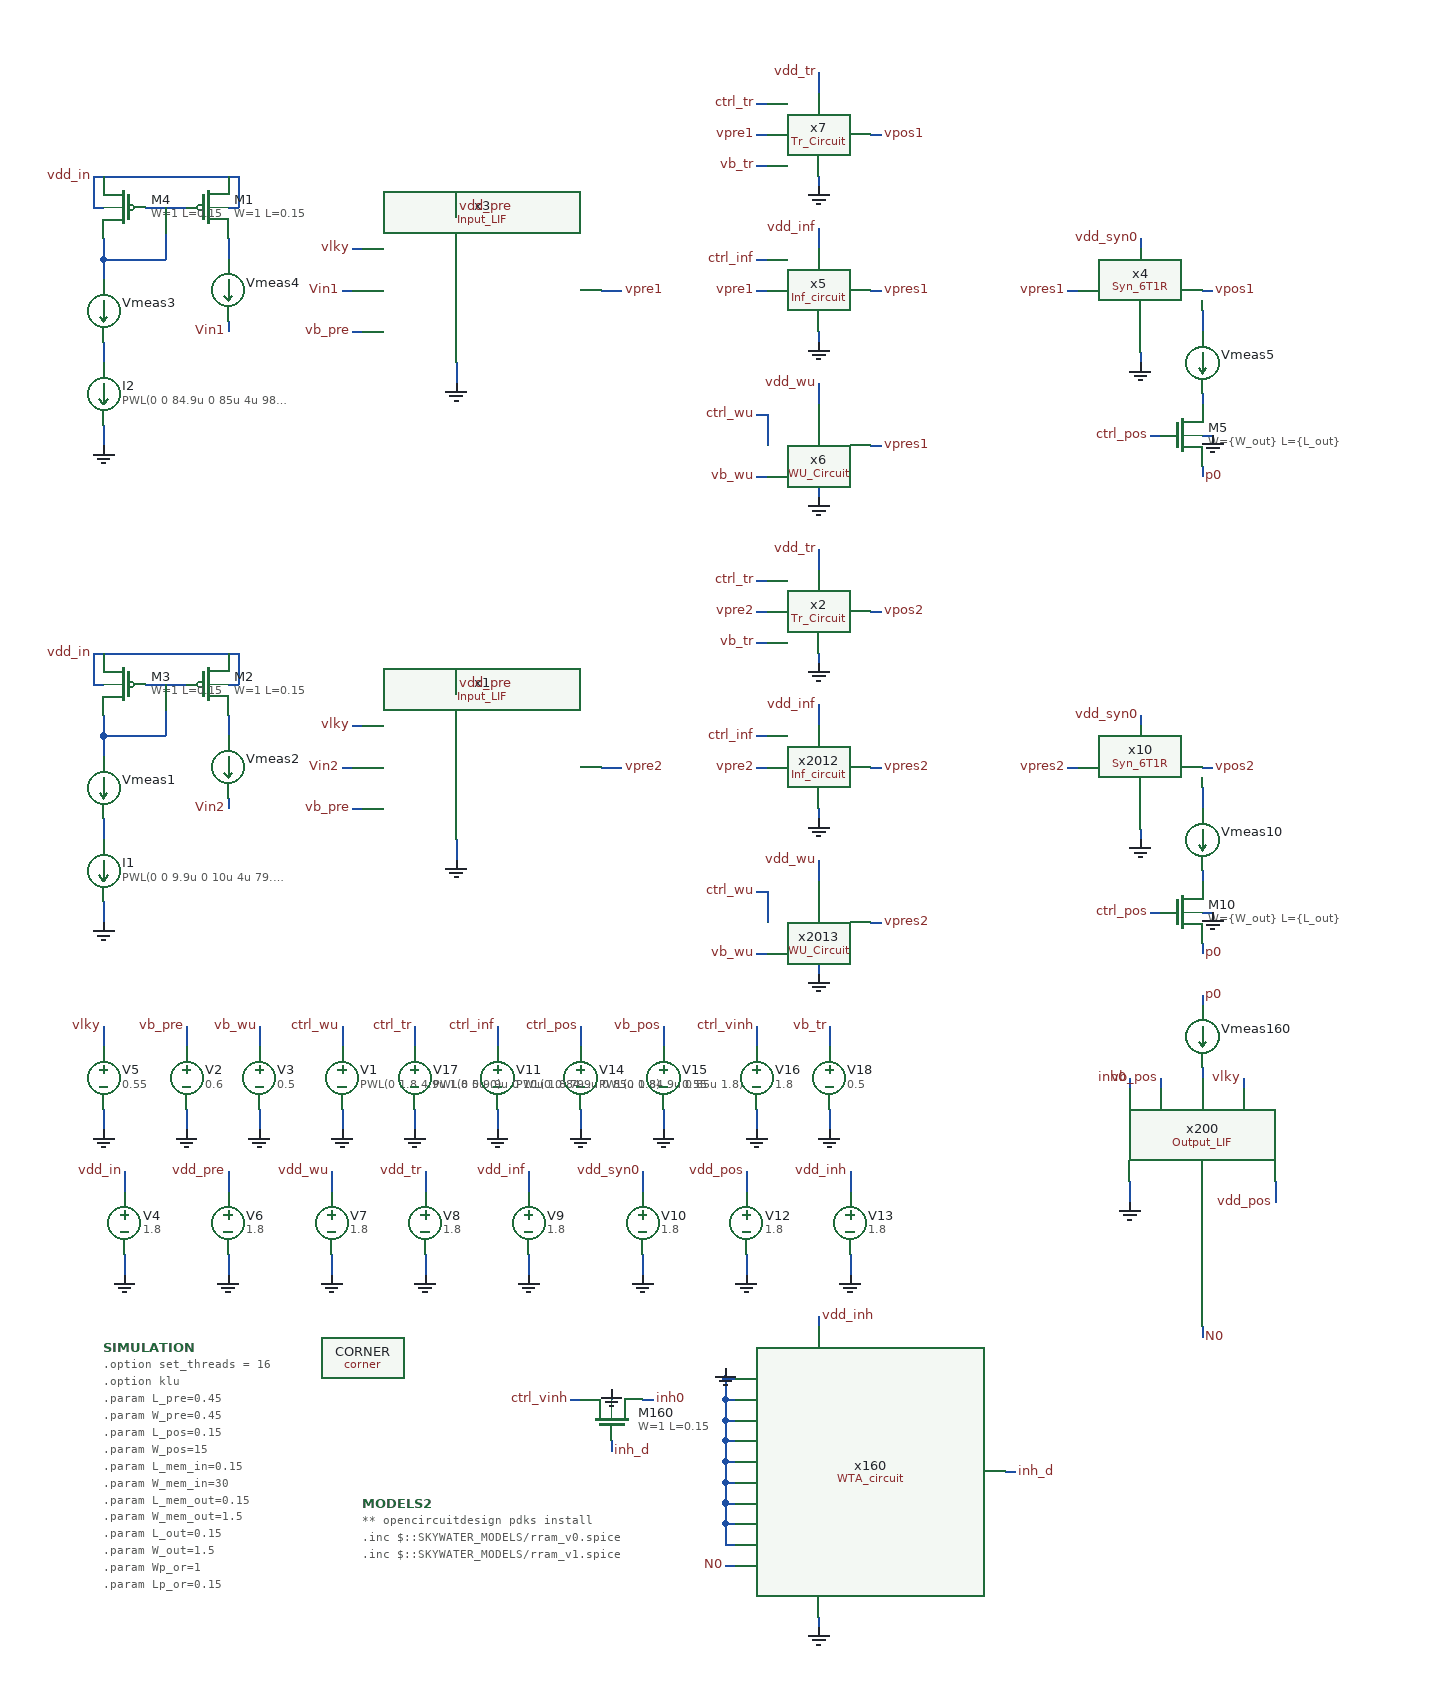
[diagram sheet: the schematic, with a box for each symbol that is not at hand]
v {xschem version=3.4.5 file_version=1.2
}
G {}
K {}
V {}
S {}
E {}
B 2 -1600 -1600 -800 -1200 {flags=graph
y1=0
y2=4e-06
ypos1=0
ypos2=2
divy=5
subdivy=1
unity=1
x1=8.43669e-05
x2=8.60304e-05
divx=5
subdivx=1
xlabmag=1.0
ylabmag=1.0


dataset=-1
unitx=1
logx=0
logy=0



color=4
node=i(Vmeas1)}
B 2 -1600 -1200 -800 -800 {flags=graph
y1=-0.14
y2=1.9
ypos1=0
ypos2=2
divy=5
subdivy=1
unity=1
x1=8.43669e-05
x2=8.60304e-05
divx=5
subdivx=1
xlabmag=1.0
ylabmag=1.0


dataset=-1
unitx=1
logx=0
logy=0
color=4
node=vpre2}
B 2 -800 -1200 0 -800 {flags=graph
y1=0
y2=1.8
ypos1=0
ypos2=2
divy=5
subdivy=1
unity=1
x1=8.43669e-05
x2=8.60304e-05
divx=5
subdivx=1
xlabmag=1.0
ylabmag=1.0


dataset=-1
unitx=1
logx=0
logy=0



color=4
node=ctrl_wu}
B 2 -800 -1600 0 -1200 {flags=graph
y1=-6.9e-07
y2=0.00031
ypos1=0
ypos2=2
divy=5
subdivy=1
unity=1
x1=8.43669e-05
x2=8.60304e-05
divx=5
subdivx=1
xlabmag=1.0
ylabmag=1.0


dataset=-1
unitx=1
logx=0
logy=0







color=17
node="\\"-1.8 i(v10) *\\""}
B 2 -1600 -800 -800 -400 {flags=graph
y1=1.1
y2=5.3
ypos1=0
ypos2=2
divy=5
subdivy=1
unity=1
x1=8.43669e-05
x2=8.60304e-05
divx=5
subdivx=1
xlabmag=1.0
ylabmag=1.0


dataset=-1
unitx=1
logx=0
logy=0

color="6 4"
node="\\"S10; 5 n.x10.xr1.n1#ngap -\\"
\\"S20; 5 n.x4.xr1.n1#ngap -\\""}
B 2 -800 -800 0 -400 {flags=graph
y1=0
y2=1.8
ypos1=0
ypos2=2
divy=5
subdivy=1
unity=1
x1=8.43669e-05
x2=8.60304e-05
divx=5
subdivx=1
xlabmag=1.0
ylabmag=1.0


dataset=-1
unitx=1
logx=0
logy=0



color="4 6 7"
node="ctrl_inf
ctrl_tr
ctrl_wu"}
B 2 -1600 -400 -800 0 {flags=graph
y1=-4.6e-07
y2=8.2e-06
ypos1=0
ypos2=2
divy=5
subdivy=1
unity=1
x1=8.43669e-05
x2=8.60304e-05
divx=5
subdivx=1
xlabmag=1.0
ylabmag=1.0


dataset=-1
unitx=1
logx=0
logy=0

color=6
node=\\"i(Vmeas160)\\"}
B 2 -800 -400 0 0 {flags=graph
y1=-0.42215
y2=1.75283
ypos1=0
ypos2=2
divy=5
subdivy=1
unity=1
x1=8.43669e-05
x2=8.60304e-05
divx=5
subdivx=1
xlabmag=1.0
ylabmag=1.0


dataset=-1
unitx=1
logx=0
logy=0

color="6 4"
node="\\"p0\\"
\\"N0\\""}
N -2320 -1060 -2300 -1060 {
lab=vpre2}
N -2720 -810 -2720 -790 {
lab=vb_pre}
N -2720 -730 -2720 -710 {
lab=GND}
N -2800 -930 -2800 -910 {
lab=GND}
N -2680 -1110 -2680 -1090 {
lab=#net1}
N -2680 -1140 -2670 -1140 {
lab=vdd_in}
N -2670 -1170 -2670 -1140 {
lab=vdd_in}
N -2680 -1170 -2670 -1170 {
lab=vdd_in}
N -2760 -1140 -2720 -1140 {
lab=#net2}
N -2800 -1170 -2680 -1170 {
lab=vdd_in}
N -2810 -1140 -2800 -1140 {
lab=vdd_in}
N -2810 -1170 -2810 -1140 {
lab=vdd_in}
N -2810 -1170 -2800 -1170 {
lab=vdd_in}
N -2800 -1110 -2800 -1090 {
lab=#net2}
N -2800 -1090 -2740 -1090 {
lab=#net2}
N -2740 -1140 -2740 -1090 {
lab=#net2}
N -2800 -1010 -2800 -990 {
lab=#net3}
N -2800 -1090 -2800 -1070 {
lab=#net2}
N -2780 -670 -2780 -650 {
lab=vdd_in}
N -2780 -590 -2780 -570 {
lab=GND}
N -2460 -990 -2460 -970 {
lab=GND}
N -2560 -1020 -2550 -1020 {
lab=vb_pre}
N -2680 -1030 -2680 -1020 {
lab=Vin2}
N -2570 -1060 -2560 -1060 {
lab=Vin2}
N -2560 -1100 -2550 -1100 {
lab=vlky}
N -2800 -810 -2800 -790 {
lab=vlky}
N -2800 -730 -2800 -710 {
lab=GND}
N -2460 -1140 -2460 -1130 {
lab=vdd_pre}
N -1800 -1000 -1800 -990 {
lab=GND}
N -1800 -1110 -1800 -1100 {
lab=vdd_syn0}
N -1740 -920 -1730 -920 {
lab=GND}
N -1740 -890 -1740 -880 {
lab=p0}
N -1870 -1060 -1860 -1060 {
lab=vpres2}
N -1740 -1060 -1730 -1060 {
lab=vpos2}
N -2110 -870 -2110 -860 {
lab=GND}
N -2060 -910 -2050 -910 {
lab=vpres2}
N -2110 -1020 -2110 -1010 {
lab=GND}
N -2060 -1060 -2050 -1060 {
lab=vpres2}
N -1790 -920 -1780 -920 {
lab=ctrl_pos}
N -2170 -880 -2160 -880 {
lab=vb_wu}
N -1740 -1040 -1740 -1020 {
lab=#net4}
N -1740 -960 -1740 -950 {
lab=#net5}
N -2170 -1090 -2160 -1090 {
lab=ctrl_inf}
N -2110 -970 -2110 -950 {
lab=vdd_wu}
N -2110 -1120 -2110 -1100 {
lab=vdd_inf}
N -2170 -940 -2160 -940 {
lab=ctrl_wu}
N -2160 -940 -2160 -910 {
lab=ctrl_wu}
N -2170 -1060 -2160 -1060 {
lab=vpre2}
N -2680 -670 -2680 -650 {
lab=vdd_pre}
N -2680 -590 -2680 -570 {
lab=GND}
N -2580 -670 -2580 -650 {
lab=vdd_wu}
N -2580 -590 -2580 -570 {
lab=GND}
N -2490 -670 -2490 -650 {
lab=vdd_tr}
N -2490 -590 -2490 -570 {
lab=GND}
N -2390 -670 -2390 -650 {
lab=vdd_inf}
N -2390 -590 -2390 -570 {
lab=GND}
N -2280 -670 -2280 -650 {
lab=vdd_syn0}
N -2280 -590 -2280 -570 {
lab=GND}
N -2570 -810 -2570 -790 {
lab=ctrl_wu}
N -2570 -730 -2570 -710 {
lab=GND}
N -2650 -810 -2650 -790 {
lab=vb_wu}
N -2650 -730 -2650 -710 {
lab=GND}
N -2420 -810 -2420 -790 {
lab=ctrl_inf}
N -2420 -730 -2420 -710 {
lab=GND}
N -1740 -770 -1740 -760 {
lab=#net6}
N -1740 -840 -1740 -830 {
lab=p0}
N -1740 -520 -1740 -510 {
lab=N0}
N -1810 -660 -1810 -640 {
lab=GND}
N -1670 -660 -1670 -640 {
lab=vdd_pos}
N -1810 -760 -1810 -750 {
lab=inh0}
N -1780 -760 -1780 -750 {
lab=vb_pos}
N -1700 -760 -1700 -750 {
lab=vlky}
N -2110 -530 -2110 -520 {
lab=vdd_inh}
N -2110 -240 -2110 -230 {
lab=GND}
N -1930 -380 -1920 -380 {
lab=inh_d}
N -2200 -290 -2190 -290 {
lab=N0}
N -2280 -450 -2270 -450 {
lab=inh0}
N -2310 -460 -2310 -450 {
lab=GND}
N -2310 -410 -2310 -400 {
lab=inh_d}
N -2350 -450 -2340 -450 {
lab=ctrl_vinh}
N -2180 -670 -2180 -650 {
lab=vdd_pos}
N -2180 -590 -2180 -570 {
lab=GND}
N -2080 -670 -2080 -650 {
lab=vdd_inh}
N -2080 -590 -2080 -570 {
lab=GND}
N -2200 -480 -2200 -470 {
lab=GND}
N -2200 -470 -2190 -470 {
lab=GND}
N -2200 -310 -2190 -310 {
lab=GND}
N -2200 -330 -2200 -310 {
lab=GND}
N -2200 -330 -2190 -330 {
lab=GND}
N -2200 -350 -2200 -330 {
lab=GND}
N -2200 -350 -2190 -350 {
lab=GND}
N -2200 -370 -2200 -350 {
lab=GND}
N -2200 -370 -2190 -370 {
lab=GND}
N -2200 -390 -2200 -370 {
lab=GND}
N -2200 -390 -2190 -390 {
lab=GND}
N -2200 -410 -2200 -390 {
lab=GND}
N -2200 -410 -2190 -410 {
lab=GND}
N -2200 -430 -2200 -410 {
lab=GND}
N -2200 -430 -2190 -430 {
lab=GND}
N -2200 -450 -2200 -430 {
lab=GND}
N -2200 -450 -2190 -450 {
lab=GND}
N -2200 -470 -2200 -450 {
lab=GND}
N -2340 -810 -2340 -790 {
lab=ctrl_pos}
N -2340 -730 -2340 -710 {
lab=GND}
N -2260 -810 -2260 -790 {
lab=vb_pos}
N -2260 -730 -2260 -710 {
lab=GND}
N -2170 -810 -2170 -790 {
lab=ctrl_vinh}
N -2170 -730 -2170 -710 {
lab=GND}
N -2110 -1170 -2110 -1160 {
lab=GND}
N -2060 -1210 -2050 -1210 {
lab=vpos2}
N -2170 -1180 -2160 -1180 {
lab=vb_tr}
N -2110 -1270 -2110 -1250 {
lab=vdd_tr}
N -2170 -1240 -2160 -1240 {
lab=ctrl_tr}
N -2170 -1210 -2160 -1210 {
lab=vpre2}
N -2500 -810 -2500 -790 {
lab=ctrl_tr}
N -2500 -730 -2500 -710 {
lab=GND}
N -2100 -810 -2100 -790 {
lab=vb_tr}
N -2100 -730 -2100 -710 {
lab=GND}
N -2320 -1520 -2300 -1520 {
lab=vpre1}
N -2800 -1390 -2800 -1370 {
lab=GND}
N -2680 -1570 -2680 -1550 {
lab=#net7}
N -2680 -1600 -2670 -1600 {
lab=vdd_in}
N -2670 -1630 -2670 -1600 {
lab=vdd_in}
N -2680 -1630 -2670 -1630 {
lab=vdd_in}
N -2760 -1600 -2720 -1600 {
lab=#net8}
N -2800 -1630 -2680 -1630 {
lab=vdd_in}
N -2810 -1600 -2800 -1600 {
lab=vdd_in}
N -2810 -1630 -2810 -1600 {
lab=vdd_in}
N -2810 -1630 -2800 -1630 {
lab=vdd_in}
N -2800 -1570 -2800 -1550 {
lab=#net8}
N -2800 -1550 -2740 -1550 {
lab=#net8}
N -2740 -1600 -2740 -1550 {
lab=#net8}
N -2800 -1470 -2800 -1450 {
lab=#net9}
N -2800 -1550 -2800 -1530 {
lab=#net8}
N -2460 -1450 -2460 -1430 {
lab=GND}
N -2560 -1480 -2550 -1480 {
lab=vb_pre}
N -2680 -1490 -2680 -1480 {
lab=Vin1}
N -2570 -1520 -2560 -1520 {
lab=Vin1}
N -2560 -1560 -2550 -1560 {
lab=vlky}
N -2460 -1600 -2460 -1590 {
lab=vdd_pre}
N -1800 -1460 -1800 -1450 {
lab=GND}
N -1800 -1570 -1800 -1560 {
lab=vdd_syn0}
N -1740 -1380 -1730 -1380 {
lab=GND}
N -1740 -1350 -1740 -1340 {
lab=p0}
N -1870 -1520 -1860 -1520 {
lab=vpres1}
N -1740 -1520 -1730 -1520 {
lab=vpos1}
N -2110 -1330 -2110 -1320 {
lab=GND}
N -2060 -1370 -2050 -1370 {
lab=vpres1}
N -2110 -1480 -2110 -1470 {
lab=GND}
N -2060 -1520 -2050 -1520 {
lab=vpres1}
N -1790 -1380 -1780 -1380 {
lab=ctrl_pos}
N -2170 -1340 -2160 -1340 {
lab=vb_wu}
N -1740 -1500 -1740 -1480 {
lab=#net10}
N -1740 -1420 -1740 -1410 {
lab=#net11}
N -2170 -1550 -2160 -1550 {
lab=ctrl_inf}
N -2110 -1430 -2110 -1410 {
lab=vdd_wu}
N -2110 -1580 -2110 -1560 {
lab=vdd_inf}
N -2170 -1400 -2160 -1400 {
lab=ctrl_wu}
N -2160 -1400 -2160 -1370 {
lab=ctrl_wu}
N -2170 -1520 -2160 -1520 {
lab=vpre1}
N -2110 -1630 -2110 -1620 {
lab=GND}
N -2060 -1670 -2050 -1670 {
lab=vpos1}
N -2170 -1640 -2160 -1640 {
lab=vb_tr}
N -2110 -1730 -2110 -1710 {
lab=vdd_tr}
N -2170 -1700 -2160 -1700 {
lab=ctrl_tr}
N -2170 -1670 -2160 -1670 {
lab=vpre1}
C {devices/gnd.sym} -2460 -970 0 0 {name=l1 lab=GND}
C {devices/lab_pin.sym} -2560 -1020 0 0 {name=p3 sig_type=std_logic lab=vb_pre}
C {devices/lab_pin.sym} -2300 -1060 2 0 {name=p5 sig_type=std_logic lab=vpre2}
C {devices/vsource.sym} -2720 -760 0 0 {name=V2 value=0.6 savecurrent=false}
C {devices/lab_pin.sym} -2720 -810 0 0 {name=p6 sig_type=std_logic lab=vb_pre}
C {devices/gnd.sym} -2720 -710 0 0 {name=l4 lab=GND}
C {devices/code_shown.sym} -2800 -500 0 0 {name=SIMULATION
only_toplevel=true
value="
.option set_threads = 16
.option klu
.param L_pre=0.45
.param W_pre=0.45
.param L_pos=0.15
.param W_pos=15
.param L_mem_in=0.15
.param W_mem_in=30
.param L_mem_out=0.15
.param W_mem_out=1.5
.param L_out=0.15
.param W_out=1.5
.param Wp_or=1
.param Lp_or=0.15
.param Wn_or=1
.param Ln_or=0.15
.param Wp_or_inv=1
.param Lp_or_inv=0.15
.param Wn_or_inv=1
.param Ln_or_inv=0.15
.control
	save all
	tran 10n 100u 0
	write Input_LIF_tb.raw
.endc
" }
C {sky130_fd_pr/corner.sym} -2550 -490 0 0 {name=CORNER only_toplevel=true corner=tt}
C {devices/isource.sym} -2800 -960 0 1 {name=I1 value="PWL(0 0 9.9u 0 10u 4u 79.9u 4u 80u 0 84.9u 0 85u 4u 989.9u 4u 990u 0)"

}
C {devices/gnd.sym} -2800 -910 0 0 {name=l20 lab=GND}
C {sky130_fd_pr/pfet_01v8.sym} -2700 -1140 0 0 {name=M2
L=0.15
W=1
nf=1
mult=1
ad="'int((nf+1)/2) * W/nf * 0.29'" 
pd="'2*int((nf+1)/2) * (W/nf + 0.29)'"
as="'int((nf+2)/2) * W/nf * 0.29'" 
ps="'2*int((nf+2)/2) * (W/nf + 0.29)'"
nrd="'0.29 / W'" nrs="'0.29 / W'"
sa=0 sb=0 sd=0
model=pfet_01v8
spiceprefix=X
}
C {sky130_fd_pr/pfet_01v8.sym} -2780 -1140 0 1 {name=M3
L=0.15
W=1
nf=1
mult=1
ad="'int((nf+1)/2) * W/nf * 0.29'" 
pd="'2*int((nf+1)/2) * (W/nf + 0.29)'"
as="'int((nf+2)/2) * W/nf * 0.29'" 
ps="'2*int((nf+2)/2) * (W/nf + 0.29)'"
nrd="'0.29 / W'" nrs="'0.29 / W'"
sa=0 sb=0 sd=0
model=pfet_01v8
spiceprefix=X
}
C {devices/lab_pin.sym} -2680 -1020 0 0 {name=p10 sig_type=std_logic lab=Vin2}
C {devices/ammeter.sym} -2800 -1040 0 0 {name=Vmeas1 savecurrent=true}
C {devices/ammeter.sym} -2680 -1060 0 0 {name=Vmeas2 savecurrent=true}
C {devices/vsource.sym} -2780 -620 0 0 {name=V4 savecurrent=false value=1.8
*"PWL(0 0 39.9u 0 40u 1.8)"}
C {devices/lab_pin.sym} -2780 -670 0 0 {name=p1 sig_type=std_logic lab=vdd_in}
C {devices/gnd.sym} -2780 -570 0 0 {name=l6 lab=GND}
C {devices/lab_pin.sym} -2570 -1060 0 0 {name=p8 sig_type=std_logic lab=Vin2}
C {devices/lab_pin.sym} -2560 -1100 0 0 {name=p11 sig_type=std_logic lab=vlky}
C {devices/vsource.sym} -2800 -760 0 0 {name=V5 savecurrent=false value=0.55}
C {devices/lab_pin.sym} -2800 -810 0 0 {name=p13 sig_type=std_logic lab=vlky}
C {devices/gnd.sym} -2800 -710 0 0 {name=l9 lab=GND}
C {devices/launcher.sym} -2480 -220 0 0 {name=h5
descr="load waves" 
tclcommand="xschem raw_read $netlist_dir/Input_LIF_tb.raw tran"
}
C {/home/ricardo/RATT_repos/Proyectos_xschem/SNN/Input_LIF.sym} -2460 -1060 0 0 {name=x1}
C {devices/lab_pin.sym} -2050 -1210 2 0 {name=p162 sig_type=std_logic lab=vpos2}
C {devices/gnd.sym} -1800 -990 0 0 {name=l39 lab=GND}
C {devices/lab_pin.sym} -1870 -1060 0 0 {name=p26 sig_type=std_logic lab=vpres2}
C {devices/ammeter.sym} -1740 -990 0 0 {name=Vmeas10 savecurrent=true}
C {sky130_fd_pr/nfet_01v8.sym} -1760 -920 0 0 {name=M10
L=\{L_out\}
W=\{W_out\}
nf=1 
mult=1
ad="'int((nf+1)/2) * W/nf * 0.29'" 
pd="'2*int((nf+1)/2) * (W/nf + 0.29)'"
as="'int((nf+2)/2) * W/nf * 0.29'" 
ps="'2*int((nf+2)/2) * (W/nf + 0.29)'"
nrd="'0.29 / W'" nrs="'0.29 / W'"
sa=0 sb=0 sd=0
model=nfet_01v8
spiceprefix=X
}
C {devices/gnd.sym} -1730 -920 3 0 {name=l8 lab=GND}
C {devices/lab_pin.sym} -1740 -880 2 0 {name=p46 sig_type=std_logic lab=p0}
C {devices/lab_pin.sym} -2050 -910 2 0 {name=p35 sig_type=std_logic lab=vpres2}
C {devices/gnd.sym} -2110 -860 0 0 {name=l18 lab=GND}
C {devices/lab_pin.sym} -2170 -1060 0 0 {name=p41 sig_type=std_logic lab=vpre2}
C {devices/lab_pin.sym} -2170 -1090 0 0 {name=p42 sig_type=std_logic lab=ctrl_inf}
C {devices/gnd.sym} -2110 -1010 0 0 {name=l10 lab=GND}
C {devices/lab_pin.sym} -2110 -970 0 0 {name=p47 sig_type=std_logic lab=vdd_wu}
C {devices/lab_pin.sym} -2110 -1120 0 0 {name=p48 sig_type=std_logic lab=vdd_inf}
C {devices/lab_pin.sym} -1790 -920 0 0 {name=p78 sig_type=std_logic lab=ctrl_pos}
C {/home/ricardo/RATT_repos/Proyectos_xschem/SNN/Syn_6T1R.sym} -1740 -880 0 0 {name=x10}
C {devices/lab_pin.sym} -1800 -1110 0 0 {name=p63 sig_type=std_logic lab=vdd_syn0}
C {/home/ricardo/RATT_repos/Proyectos_xschem/SNN/Inf_circuit.sym} -2110 -1060 0 0 {name=x2012}
C {/home/ricardo/RATT_repos/Proyectos_xschem/SNN/WU_Circuit.sym} -2110 -910 0 0 {name=x2013}
C {devices/lab_pin.sym} -2170 -940 0 0 {name=p36 sig_type=std_logic lab=ctrl_wu}
C {devices/lab_pin.sym} -2170 -880 0 0 {name=p283 sig_type=std_logic lab=vb_wu}
C {devices/lab_pin.sym} -1730 -1060 2 0 {name=p405 sig_type=std_logic lab=vpos2}
C {devices/vsource.sym} -2680 -620 0 0 {name=V6 savecurrent=false value=1.8
*"PWL(0 0 39.9u 0 40u 1.8)"}
C {devices/lab_pin.sym} -2680 -670 0 0 {name=p2 sig_type=std_logic lab=vdd_pre}
C {devices/gnd.sym} -2680 -570 0 0 {name=l11 lab=GND}
C {devices/vsource.sym} -2580 -620 0 0 {name=V7 
value=1.8}
C {devices/gnd.sym} -2580 -570 0 0 {name=l3 lab=GND}
C {devices/lab_pin.sym} -2810 -1170 0 0 {name=p4 sig_type=std_logic lab=vdd_in}
C {devices/lab_pin.sym} -2580 -670 0 0 {name=p9 sig_type=std_logic lab=vdd_wu}
C {devices/vsource.sym} -2490 -620 0 0 {name=V8 
value=1.8}
C {devices/gnd.sym} -2490 -570 0 0 {name=l7 lab=GND}
C {devices/lab_pin.sym} -2490 -670 0 0 {name=p12 sig_type=std_logic lab=vdd_tr}
C {devices/vsource.sym} -2390 -620 0 0 {name=V9 
value=1.8}
C {devices/gnd.sym} -2390 -570 0 0 {name=l12 lab=GND}
C {devices/lab_pin.sym} -2390 -670 0 0 {name=p14 sig_type=std_logic lab=vdd_inf}
C {devices/vsource.sym} -2280 -620 0 0 {name=V10 
value=1.8}
C {devices/gnd.sym} -2280 -570 0 0 {name=l14 lab=GND}
C {devices/lab_pin.sym} -2280 -670 0 0 {name=p15 sig_type=std_logic lab=vdd_syn0}
C {devices/lab_pin.sym} -2460 -1140 2 0 {name=p7 sig_type=std_logic lab=vdd_pre}
C {devices/vsource.sym} -2570 -760 0 0 {name=V1 savecurrent=false value="PWL(0 1.8 4.9u 1.8 5u 0)"}
C {devices/lab_pin.sym} -2570 -810 0 0 {name=p16 sig_type=std_logic lab=ctrl_wu}
C {devices/gnd.sym} -2570 -710 0 0 {name=l2 lab=GND}
C {devices/vsource.sym} -2650 -760 0 0 {name=V3 savecurrent=false value=0.5}
C {devices/lab_pin.sym} -2650 -810 0 0 {name=p17 sig_type=std_logic lab=vb_wu}
C {devices/gnd.sym} -2650 -710 0 0 {name=l5 lab=GND}
C {devices/vsource.sym} -2420 -760 0 0 {name=V11 savecurrent=false value="PWL(0 0 84.9u 0 85u 1.8)"}
C {devices/lab_pin.sym} -2420 -810 0 0 {name=p18 sig_type=std_logic lab=ctrl_inf}
C {devices/gnd.sym} -2420 -710 0 0 {name=l15 lab=GND}
C {devices/lab_pin.sym} -1780 -760 1 0 {name=p19 sig_type=std_logic lab=vb_pos}
C {devices/gnd.sym} -1810 -640 0 0 {name=l16 lab=GND}
C {devices/ammeter.sym} -1740 -800 0 0 {name=Vmeas160 savecurrent=true}
C {devices/lab_pin.sym} -1740 -840 2 0 {name=p20 sig_type=std_logic lab=p0}
C {devices/lab_pin.sym} -1740 -510 2 0 {name=p21 sig_type=std_logic lab=N0}
C {devices/lab_pin.sym} -1670 -640 3 0 {name=p22 sig_type=std_logic lab=vdd_pos}
C {devices/lab_pin.sym} -1810 -760 1 0 {name=p23 sig_type=std_logic lab=inh0}
C {devices/lab_pin.sym} -1700 -760 1 0 {name=p24 sig_type=std_logic lab=vlky}
C {/home/ricardo/RATT_repos/Proyectos_xschem/SNN/Output_LIF.sym} -1740 -660 1 0 {name=x200}
C {devices/gnd.sym} -2110 -230 0 0 {name=l27 lab=GND}
C {devices/lab_pin.sym} -2110 -530 2 0 {name=p81 sig_type=std_logic lab=vdd_inh}
C {devices/lab_pin.sym} -1920 -380 2 0 {name=p91 sig_type=std_logic lab=inh_d}
C {/home/ricardo/RATT_repos/Proyectos_xschem/inhibitory/WTA_circuit.sym} -2070 -380 0 0 {name=x160}
C {devices/lab_pin.sym} -2200 -290 0 0 {name=p25 sig_type=std_logic lab=N0}
C {devices/lab_pin.sym} -2270 -450 2 0 {name=p31 sig_type=std_logic lab=inh0}
C {sky130_fd_pr/nfet_01v8.sym} -2310 -430 3 0 {name=M160
L=0.15
W=1
nf=1 
mult=1
ad="'int((nf+1)/2) * W/nf * 0.29'" 
pd="'2*int((nf+1)/2) * (W/nf + 0.29)'"
as="'int((nf+2)/2) * W/nf * 0.29'" 
ps="'2*int((nf+2)/2) * (W/nf + 0.29)'"
nrd="'0.29 / W'" nrs="'0.29 / W'"
sa=0 sb=0 sd=0
model=nfet_01v8
spiceprefix=X
}
C {devices/gnd.sym} -2310 -460 2 0 {name=l21 lab=GND}
C {devices/lab_pin.sym} -2310 -400 2 0 {name=p32 sig_type=std_logic lab=inh_d}
C {devices/lab_pin.sym} -2350 -450 0 0 {name=p45 sig_type=std_logic lab=ctrl_vinh}
C {devices/vsource.sym} -2180 -620 0 0 {name=V12 
value=1.8}
C {devices/gnd.sym} -2180 -570 0 0 {name=l17 lab=GND}
C {devices/lab_pin.sym} -2180 -670 0 0 {name=p27 sig_type=std_logic lab=vdd_pos}
C {devices/vsource.sym} -2080 -620 0 0 {name=V13 
value=1.8}
C {devices/gnd.sym} -2080 -570 0 0 {name=l19 lab=GND}
C {devices/lab_pin.sym} -2080 -670 0 0 {name=p28 sig_type=std_logic lab=vdd_inh}
C {devices/gnd.sym} -2200 -480 2 0 {name=l22 lab=GND}
C {devices/vsource.sym} -2340 -760 0 0 {name=V14 savecurrent=false value="PWL(0 0 84.9u 0 85u 1.8)"}
C {devices/lab_pin.sym} -2340 -810 0 0 {name=p29 sig_type=std_logic lab=ctrl_pos}
C {devices/gnd.sym} -2340 -710 0 0 {name=l23 lab=GND}
C {devices/vsource.sym} -2260 -760 0 0 {name=V15 savecurrent=false value=0.55}
C {devices/lab_pin.sym} -2260 -810 0 0 {name=p30 sig_type=std_logic lab=vb_pos}
C {devices/gnd.sym} -2260 -710 0 0 {name=l24 lab=GND}
C {devices/vsource.sym} -2170 -760 0 0 {name=V16 savecurrent=false value=1.8}
C {devices/lab_pin.sym} -2170 -810 0 0 {name=p33 sig_type=std_logic lab=ctrl_vinh}
C {devices/gnd.sym} -2170 -710 0 0 {name=l25 lab=GND}
C {devices/code.sym} -2550 -350 0 0 {name=MODELS2
only_toplevel=true
format="tcleval( @value )"
value="
** opencircuitdesign pdks install
.inc $::SKYWATER_MODELS/rram_v0.spice
.inc $::SKYWATER_MODELS/rram_v1.spice
"
spice_ignore=false}
C {/home/ricardo/RATT_repos/Proyectos_xschem/SNN/Tr_Circuit.sym} -2110 -1210 0 0 {name=x2}
C {devices/lab_pin.sym} -2050 -1060 2 0 {name=p34 sig_type=std_logic lab=vpres2}
C {devices/gnd.sym} -2110 -1160 0 0 {name=l13 lab=GND}
C {devices/lab_pin.sym} -2110 -1270 0 0 {name=p37 sig_type=std_logic lab=vdd_tr}
C {devices/lab_pin.sym} -2170 -1240 0 0 {name=p38 sig_type=std_logic lab=ctrl_tr}
C {devices/lab_pin.sym} -2170 -1180 0 0 {name=p39 sig_type=std_logic lab=vb_tr}
C {devices/vsource.sym} -2500 -760 0 0 {name=V17 savecurrent=false value="PWL(0 0 9.9u 0 10u 1.8 79.9u 1.8 80u 0)"}
C {devices/lab_pin.sym} -2500 -810 0 0 {name=p43 sig_type=std_logic lab=ctrl_tr}
C {devices/gnd.sym} -2500 -710 0 0 {name=l26 lab=GND}
C {devices/vsource.sym} -2100 -760 0 0 {name=V18 savecurrent=false value=0.5}
C {devices/lab_pin.sym} -2100 -810 0 0 {name=p44 sig_type=std_logic lab=vb_tr}
C {devices/gnd.sym} -2100 -710 0 0 {name=l28 lab=GND}
C {devices/lab_pin.sym} -2170 -1210 0 0 {name=p40 sig_type=std_logic lab=vpre2}
C {devices/gnd.sym} -2460 -1430 0 0 {name=l29 lab=GND}
C {devices/lab_pin.sym} -2560 -1480 0 0 {name=p49 sig_type=std_logic lab=vb_pre}
C {devices/lab_pin.sym} -2300 -1520 2 0 {name=p50 sig_type=std_logic lab=vpre1}
C {devices/isource.sym} -2800 -1420 0 1 {name=I2 value="PWL(0 0 84.9u 0 85u 4u 989.9u 4u 990u 0)"

}
C {devices/gnd.sym} -2800 -1370 0 0 {name=l30 lab=GND}
C {sky130_fd_pr/pfet_01v8.sym} -2700 -1600 0 0 {name=M1
L=0.15
W=1
nf=1
mult=1
ad="'int((nf+1)/2) * W/nf * 0.29'" 
pd="'2*int((nf+1)/2) * (W/nf + 0.29)'"
as="'int((nf+2)/2) * W/nf * 0.29'" 
ps="'2*int((nf+2)/2) * (W/nf + 0.29)'"
nrd="'0.29 / W'" nrs="'0.29 / W'"
sa=0 sb=0 sd=0
model=pfet_01v8
spiceprefix=X
}
C {sky130_fd_pr/pfet_01v8.sym} -2780 -1600 0 1 {name=M4
L=0.15
W=1
nf=1
mult=1
ad="'int((nf+1)/2) * W/nf * 0.29'" 
pd="'2*int((nf+1)/2) * (W/nf + 0.29)'"
as="'int((nf+2)/2) * W/nf * 0.29'" 
ps="'2*int((nf+2)/2) * (W/nf + 0.29)'"
nrd="'0.29 / W'" nrs="'0.29 / W'"
sa=0 sb=0 sd=0
model=pfet_01v8
spiceprefix=X
}
C {devices/lab_pin.sym} -2680 -1480 0 0 {name=p51 sig_type=std_logic lab=Vin1}
C {devices/ammeter.sym} -2800 -1500 0 0 {name=Vmeas3 savecurrent=true}
C {devices/ammeter.sym} -2680 -1520 0 0 {name=Vmeas4 savecurrent=true}
C {devices/lab_pin.sym} -2570 -1520 0 0 {name=p52 sig_type=std_logic lab=Vin1}
C {devices/lab_pin.sym} -2560 -1560 0 0 {name=p53 sig_type=std_logic lab=vlky}
C {/home/ricardo/RATT_repos/Proyectos_xschem/SNN/Input_LIF.sym} -2460 -1520 0 0 {name=x3}
C {devices/lab_pin.sym} -2050 -1670 2 0 {name=p54 sig_type=std_logic lab=vpos1}
C {devices/gnd.sym} -1800 -1450 0 0 {name=l31 lab=GND}
C {devices/lab_pin.sym} -1870 -1520 0 0 {name=p55 sig_type=std_logic lab=vpres1}
C {devices/ammeter.sym} -1740 -1450 0 0 {name=Vmeas5 savecurrent=true}
C {sky130_fd_pr/nfet_01v8.sym} -1760 -1380 0 0 {name=M5
L=\{L_out\}
W=\{W_out\}
nf=1 
mult=1
ad="'int((nf+1)/2) * W/nf * 0.29'" 
pd="'2*int((nf+1)/2) * (W/nf + 0.29)'"
as="'int((nf+2)/2) * W/nf * 0.29'" 
ps="'2*int((nf+2)/2) * (W/nf + 0.29)'"
nrd="'0.29 / W'" nrs="'0.29 / W'"
sa=0 sb=0 sd=0
model=nfet_01v8
spiceprefix=X
}
C {devices/gnd.sym} -1730 -1380 3 0 {name=l32 lab=GND}
C {devices/lab_pin.sym} -1740 -1340 2 0 {name=p56 sig_type=std_logic lab=p0}
C {devices/lab_pin.sym} -2050 -1370 2 0 {name=p57 sig_type=std_logic lab=vpres1}
C {devices/gnd.sym} -2110 -1320 0 0 {name=l33 lab=GND}
C {devices/lab_pin.sym} -2170 -1520 0 0 {name=p58 sig_type=std_logic lab=vpre1}
C {devices/lab_pin.sym} -2170 -1550 0 0 {name=p59 sig_type=std_logic lab=ctrl_inf}
C {devices/gnd.sym} -2110 -1470 0 0 {name=l34 lab=GND}
C {devices/lab_pin.sym} -2110 -1430 0 0 {name=p60 sig_type=std_logic lab=vdd_wu}
C {devices/lab_pin.sym} -2110 -1580 0 0 {name=p61 sig_type=std_logic lab=vdd_inf}
C {devices/lab_pin.sym} -1790 -1380 0 0 {name=p62 sig_type=std_logic lab=ctrl_pos}
C {/home/ricardo/RATT_repos/Proyectos_xschem/SNN/Syn_6T1R.sym} -1740 -1340 0 0 {name=x4}
C {devices/lab_pin.sym} -1800 -1570 0 0 {name=p64 sig_type=std_logic lab=vdd_syn0}
C {/home/ricardo/RATT_repos/Proyectos_xschem/SNN/Inf_circuit.sym} -2110 -1520 0 0 {name=x5}
C {/home/ricardo/RATT_repos/Proyectos_xschem/SNN/WU_Circuit.sym} -2110 -1370 0 0 {name=x6}
C {devices/lab_pin.sym} -2170 -1400 0 0 {name=p65 sig_type=std_logic lab=ctrl_wu}
C {devices/lab_pin.sym} -2170 -1340 0 0 {name=p66 sig_type=std_logic lab=vb_wu}
C {devices/lab_pin.sym} -1730 -1520 2 0 {name=p67 sig_type=std_logic lab=vpos1}
C {devices/lab_pin.sym} -2810 -1630 0 0 {name=p68 sig_type=std_logic lab=vdd_in}
C {devices/lab_pin.sym} -2460 -1600 2 0 {name=p69 sig_type=std_logic lab=vdd_pre}
C {/home/ricardo/RATT_repos/Proyectos_xschem/SNN/Tr_Circuit.sym} -2110 -1670 0 0 {name=x7}
C {devices/lab_pin.sym} -2050 -1520 2 0 {name=p70 sig_type=std_logic lab=vpres1}
C {devices/gnd.sym} -2110 -1620 0 0 {name=l35 lab=GND}
C {devices/lab_pin.sym} -2110 -1730 0 0 {name=p71 sig_type=std_logic lab=vdd_tr}
C {devices/lab_pin.sym} -2170 -1700 0 0 {name=p72 sig_type=std_logic lab=ctrl_tr}
C {devices/lab_pin.sym} -2170 -1640 0 0 {name=p73 sig_type=std_logic lab=vb_tr}
C {devices/lab_pin.sym} -2170 -1670 0 0 {name=p74 sig_type=std_logic lab=vpre1}
